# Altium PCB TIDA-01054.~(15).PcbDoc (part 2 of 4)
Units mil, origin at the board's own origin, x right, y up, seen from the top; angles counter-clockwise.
Board outline 4448 x 3930 mil, 4 copper layers (Layer 1 - Top Layer, Layer 2 - GND, Layer 3 - PWR, Layer 4 - Bottom Layer), stack 59.034 mil thick; 537 components, 284 nets, 1540 pads, 769 vias.
Unrouted connection lines stored in the file: 1.

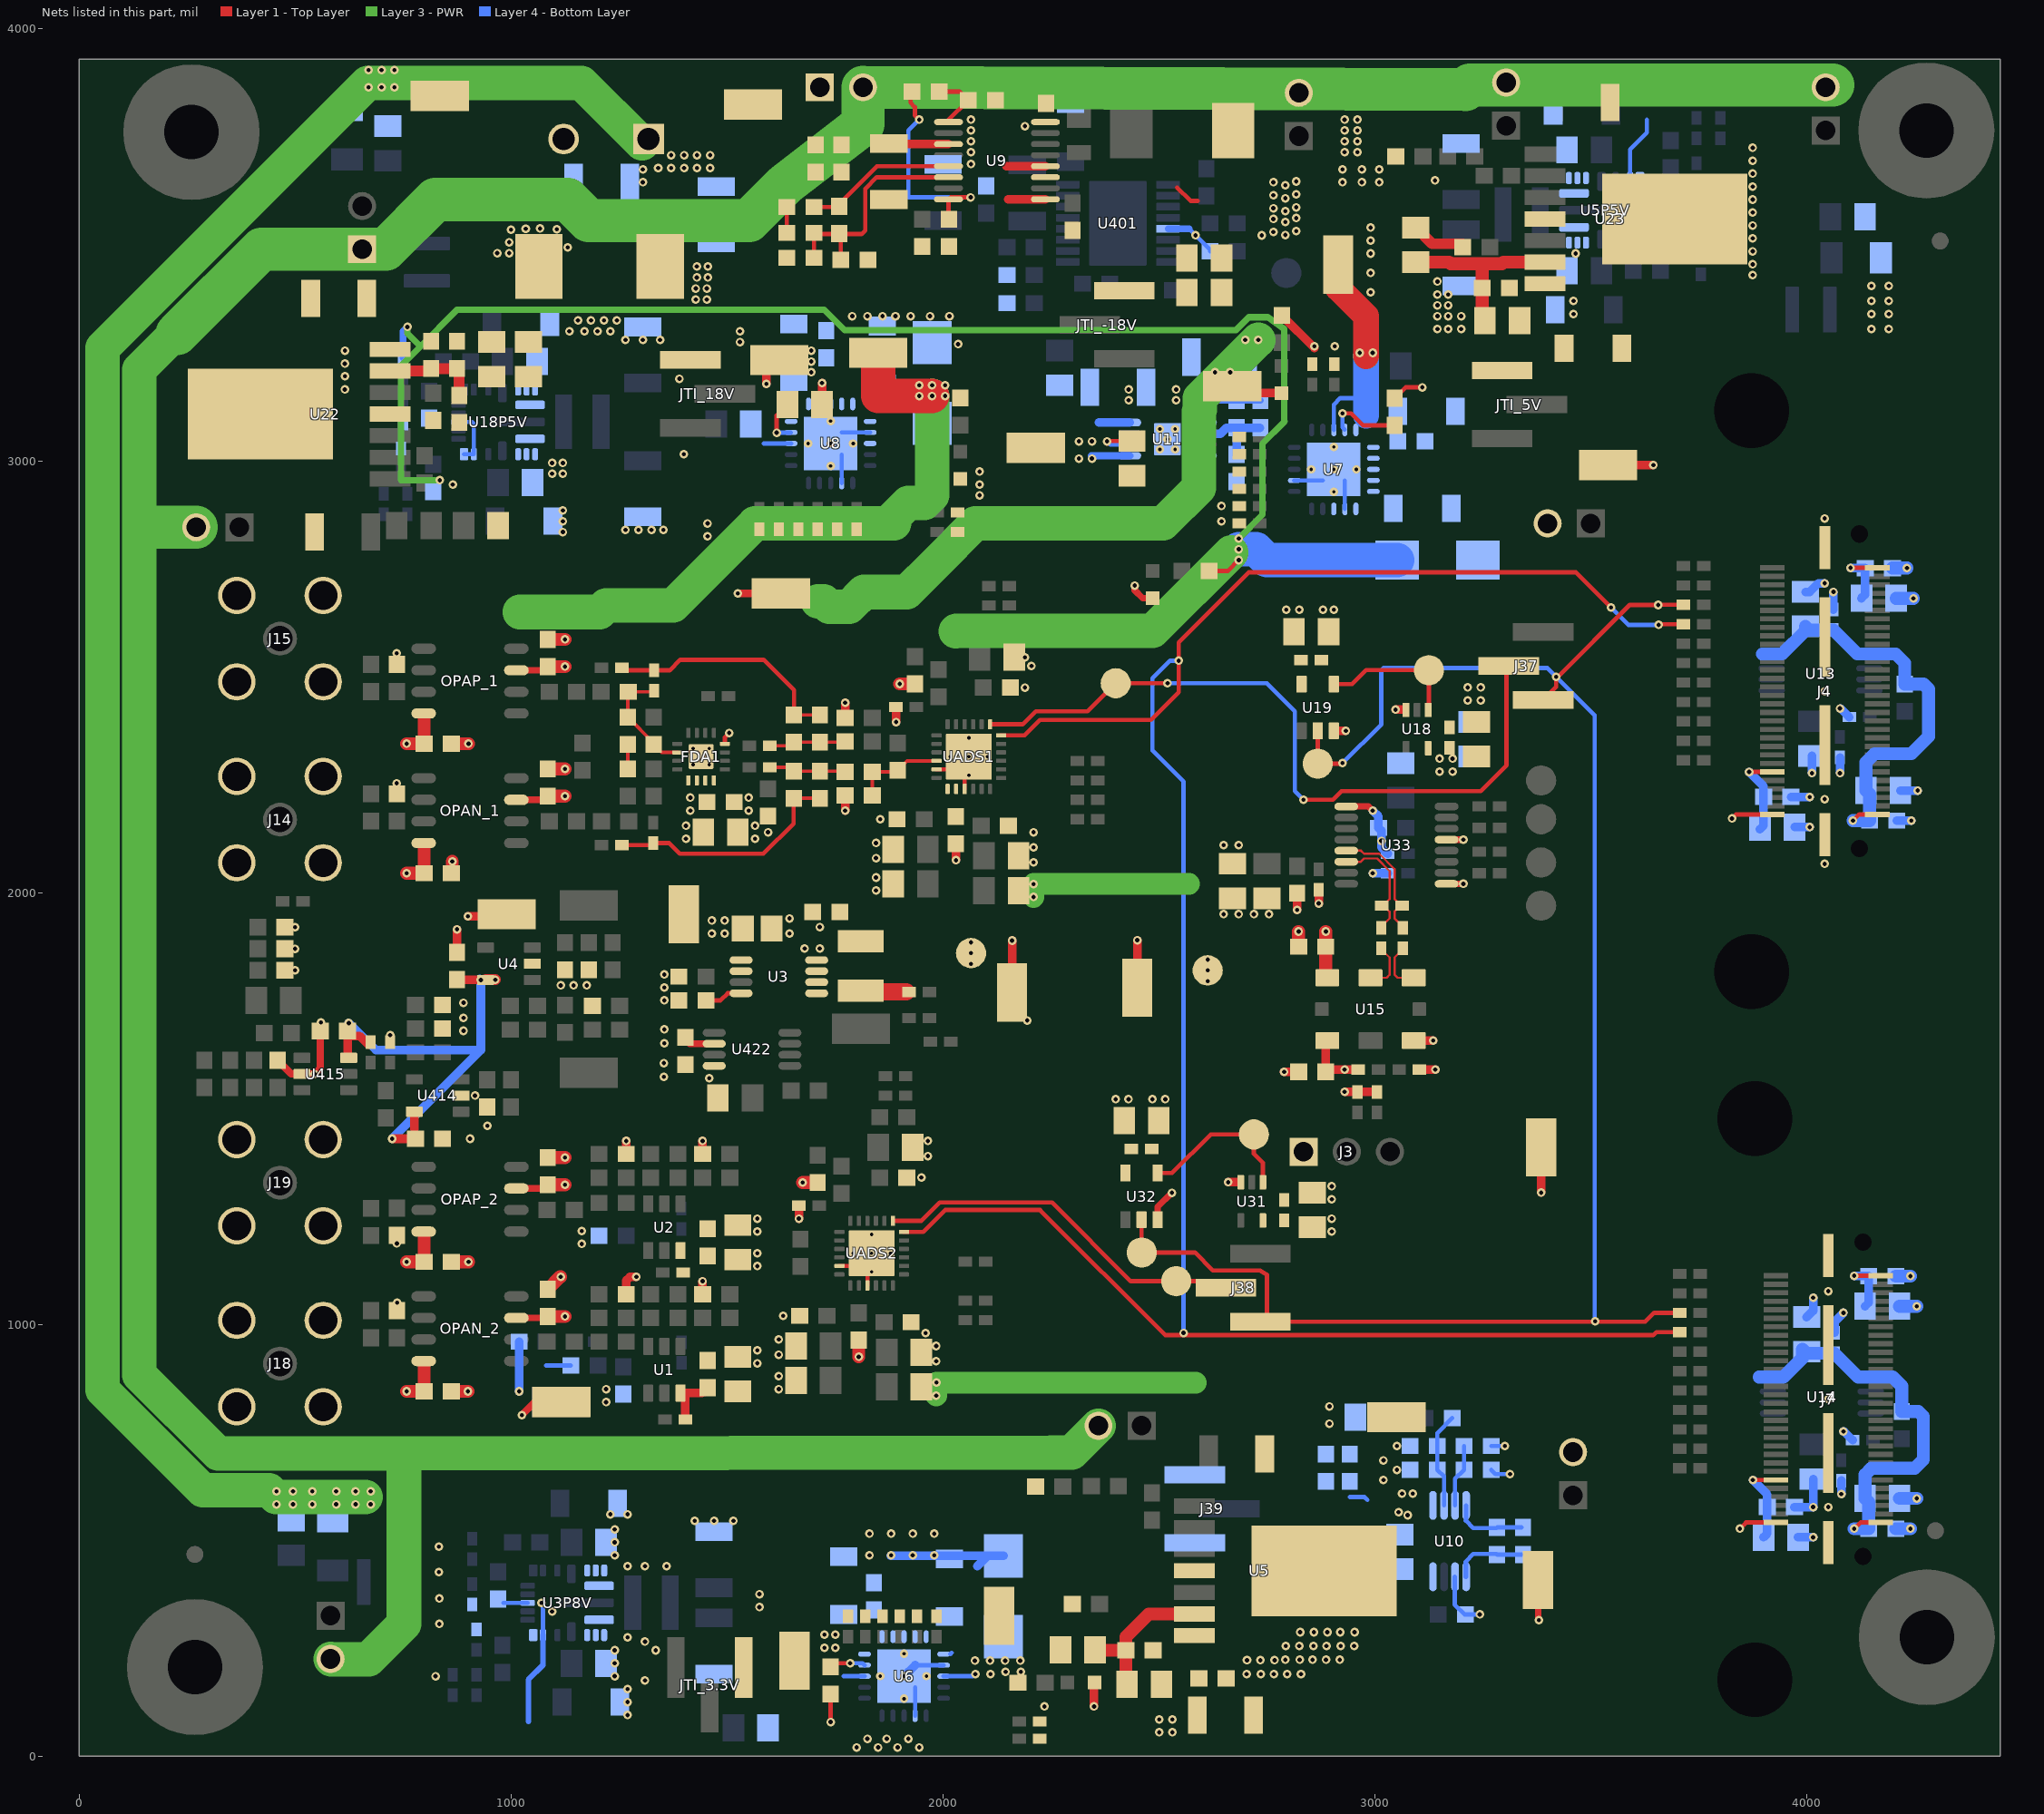
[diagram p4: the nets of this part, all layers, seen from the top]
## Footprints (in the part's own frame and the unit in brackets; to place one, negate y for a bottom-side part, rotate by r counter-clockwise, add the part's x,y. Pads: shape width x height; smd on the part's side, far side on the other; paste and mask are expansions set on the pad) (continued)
RNL0022A_NV [mm] "VQFN, 22 pin, 0.5 mm pitch"
  rrect25% 0.7x0.5 smd paste-0.05 mask-0.05: 1(-1.9,2) 17(1.9,2)
  rrect40% 0.7x0.35 smd paste-0.05 mask-0.05: 2(-1.9,1.425) 3(-1.9,0.575) 15(1.9,0.575) 16(1.9,1.425)
  rrect40% 1.1x0.5 smd paste-0.25 mask-0.05: 4(-1.7,-0.25) 14(1.7,-0.25)
  rrect25% 0.4x0.4 on Bottom Paste: 4A(-2,-0.25) 4B(-1.4,-0.25) 14A(1.4,-0.25) 14B(2,-0.25)
  rrect57% 0.7x0.35 smd paste-0.05 mask-0.05: 5(-1.9,-1.175) 6(-1.9,-1.675) 7(-1.9,-2.175) 11(1.9,-2.175) 12(1.9,-1.675) 13(1.9,-1.175)
  rrect40% 0.5x1.74 smd paste-0.25 mask-0.05: 8(-1,-1.875) 10(1,-1.875)
  rrect25% 0.4x0.66 on Bottom Paste: 8A(-1,-1.445) 8B(-1,-2.305) 10A(1,-1.445) 10B(1,-2.305)
  rrect40% 0.5x3.25 smd paste-0.25 mask-0.05: 9(0,-1.125)
  rrect25% 0.4x0.63 on Bottom Paste: 9A(0,0.12) 9B(0,-0.71) 9C(0,-1.54) 9D(0,-2.37)
  rrect40% 0.35x0.85 smd paste-0.05 mask-0.05: 18(1,2.325) 19(0.5,2.325) 20(0,2.325) 21(-0.5,2.325) 22(-1,2.325)
  silkscreen extent -2.15,-2.65 2.15,2.65, body extent -2,-2.5 2,2.5, height 0.9
Samtec_QTH-030-01-x-D-A [mil] "Header (Shrouded), 19.7mil, 30x2, SMT"
  rect 12x57 smd mask+1: 1(-285.7,121.5) 2(-285.7,-121.5) 3(-266,121.5) 4(-266,-121.5) 5(-246.3,121.5) 6(-246.3,-121.5) 7(-226.6,121.5) 8(-226.6,-121.5) 9(-206.9,121.5) 10(-206.9,-121.5) 11(-187.2,121.5) 12(-187.2,-121.5) 13(-167.5,121.5) 14(-167.5,-121.5) 15(-147.8,121.5) 16(-147.8,-121.5) 17(-128.1,121.5) 18(-128.1,-121.5) 19(-108.4,121.5) 20(-108.4,-121.5) 21(-88.7,121.5) 22(-88.7,-121.5) 23(-69,121.5) 24(-69,-121.5) 25(-49.3,121.5) 26(-49.3,-121.5) 27(-29.6,121.5) 28(-29.6,-121.5) 29(-9.9,121.5) 30(-9.9,-121.5) 31(9.8,121.5) 32(9.8,-121.5) 33(29.5,121.5) 34(29.5,-121.5) 35(49.2,121.5) 36(49.2,-121.5) 37(68.9,121.5) 38(68.9,-121.5) 39(88.6,121.5) 40(88.6,-121.5) 41(108.3,121.5) 42(108.3,-121.5) 43(128,121.5) 44(128,-121.5) 45(147.7,121.5) 46(147.7,-121.5) 47(167.4,121.5) 48(167.4,-121.5) 49(187.1,121.5) 50(187.1,-121.5) 51(206.8,121.5) 52(206.8,-121.5) 53(226.5,121.5) 54(226.5,-121.5) 55(246.2,121.5) 56(246.2,-121.5) 57(265.9,121.5) 58(265.9,-121.5) 59(285.6,121.5) 60(285.6,-121.5)
  round 0 hole 40 unplated mask+1: MH1(-364,80) MH2(364,80)
  rect 100x25 smd mask+1: MP1(-332.7,0) MP4(332.3,0)
  rect 185x25 smd mask+1: MP2(-125.2,0) MP3(124.8,0)
  silkscreen extent -394,-118 394,131, body extent -394,-140 394,140, height 170
Samtec_TMM-103-01-x-S-SM [mm] "Header,2mm, 3x1, SMT"
  rect 1.02x3.56 smd: 1(-2,1.015) 2(0,-1.015) 3(2,1.015)
  silkscreen extent -3.2,-0.99 3,0.99, body extent -3,-2.41 3,2.41, height 5.97
SIA0008B [mm] "SIP 8-Leads, Body 5x7mm"
  rrect17% 1x0.6 on Top Paste: 1(-1.85,2.14) 1(-1.85,2.94) 2(-1.85,-0.4) 2(-1.85,0.4) 3(-1.85,-2.94) 3(-1.85,-2.14) 4(1.85,-2.94) 4(1.85,-2.14) 5(1.85,-0.4) 5(1.85,0.4) 6(1.85,2.14) 6(1.85,2.94)
  rrect10% 1x1.4 smd paste-0.5: 1(-1.85,2.54) 2(-1.85,0) 3(-1.85,-2.54) 4(1.85,-2.54) 5(1.85,0) 6(1.85,2.54)
  rrect12% 0.8x0.8 smd: 7(0,2.865) 8(0,-2.865)
  silkscreen extent -2.64,-3.63 2.64,3.63, body extent -2.56,-3.56 2.56,3.56, height 1.13
SMC [mil] "Molded Diode, 2-Leads, Body 6.9x5.8mm, IPC Medium Density, based on OnSemi component dimensions and land patterns"
  rect 110x150 smd: 1(-140.49,0) 2(140.49,0)
  silkscreen extent -221,-124 189,123, body extent -156,-116 156,116, height 91
Testpoint_Keystone_Miniature [mil] "Miniature SMT test point"
  rect 135x70 smd: 1(0,0)
  silkscreen extent -78,-46 78,45, body extent -52,-20 52,20, height 61
TI_Stacked_Overlay_Small [mil]
  silkscreen extent -418,-98 418,98
TSOP65P640X120-8N [mm] "TSOP, 8-Leads, Body 3.1x4.5mm (max), Pitch 0.65mm, IPC Medium Density"
  oval 1.55x0.35 smd mask+0.08: 1(-2.875,0.975) 2(-2.875,0.325) 3(-2.875,-0.325) 4(-2.875,-0.975) 5(2.875,-0.975) 6(2.875,-0.325) 7(2.875,0.325) 8(2.875,0.975)
  silkscreen extent -1.7,-1.55 1.7,1.55, body extent -2.25,-1.55 2.25,1.55, height 1.21
TZA07A_V [mm] "D2-PAK, 8-Leads, Body 9.9x10.2mm, Pitch 1.27mm, Lead Span 13.8mm, NSC Recommended"
  rect 2.41x0.89 smd: 1(-5.35,3.81) 2(-5.35,2.54) 3(-5.35,1.27) 4(-5.35,0) 5(-5.35,-1.27) 6(-5.35,-2.54) 7(-5.35,-3.81)
  rect 8.54x5.35 smd: 8(2.28,0)
  silkscreen extent -5.47,-5.15 -2.7,5.15, body extent -2.55,-5.2 7.55,5.2, height 4.67
WE-TPC_2828 [mm] "WURTH"
  rect 1x3.2 smd: 1(-1.1,0) 2(1.1,0)
  body extent -1.5,-1.5 1.5,1.5, height 3
WE-TPC_3816 [mm] "WERTH"
  rect 0.5x0.5 smd: 1(-1.75,0) 2(1.75,0.05)
  Layer 1 - Top Layer region: 0.55,2.15 2.15,2.15 2.15,-2.15 0.55,-2.15 0.55,-1.35 0.56,-1.173 1.015,-0.813 1.267,-0.29 1.267,0.29 1.015,0.813 0.56,1.173 0.56,1.173 0.55,1.4
  Layer 1 - Top Layer region: -0.55,-2.15 -2.15,-2.15 -2.15,2.15 -0.55,2.15 -0.55,1.35 -0.56,1.173 -1.015,0.813 -1.267,0.29 -1.267,-0.29 -1.015,-0.813 -0.56,-1.173 -0.56,-1.173 -0.55,-1.4
  silkscreen extent -0.3,-2.15 0.3,2.15, body extent -2.05,-2.05 2.05,2.05, height 1.8
WL-SMCW_RED [mm] "WURTH"
  rect 0.8x0.8 smd: 1(-0.8,0) 2(0.8,0)
  silkscreen extent -1.9,-0.8 1.2,0.8, body extent -0.85,-0.45 0.85,0.45, height 0.8
WURTH_61300211121 [mm] "Header, 2.54mm, 2x1, TH"
  rect 1.65x1.65 hole 1.15: 1(-1.27,0)
  round 1.65 hole 1.15: 2(1.27,0)
  silkscreen extent -2.54,-1.27 2.54,1.6, body extent -2.54,-1.27 2.54,1.27, height 8.54
WURTH_61300311121 [mm] "Header, 2.54mm, 3x1, TH"
  rect 1.65x1.65 hole 1.15: 1(-2.54,0)
  round 1.65 hole 1.15: 2(0,0) 3(2.54,0)
  silkscreen extent -3.81,-1.27 3.81,1.6, body extent -3.81,-1.27 3.81,1.27, height 8.54
Wurth_691213710002 [mm] "TH, 2-Leads, Body 10x8.3mm, Pitch 5mm"
  rect 1.8x1.8 hole 1.3: 1(-2.5,0)
  round 1.8 hole 1.3: 2(2.5,0)
  silkscreen extent -5,-4.75 5,4.15, body extent -5.6,-4.15 5,4.15, height 10
Wurth_WA-SMSI [mm] "ROUND STANDOFF M3 STEEL 5MM"
  round 0 hole 4.4 unplated: ""(0,0)
  Layer 1 - Top Layer region: -3.711,0 -3.666,-0.581 -3.53,-1.147 -3.307,-1.685 -3.003,-2.182 -2.624,-2.624 -2.182,-3.003 -1.685,-3.307 -1.147,-3.53 -0.581,-3.666 0,-3.711 0.581,-3.666 1.147,-3.53 1.685,-3.307 2.182,-3.003 2.624,-2.624 3.003,-2.182 3.307,-1.685 3.53,-1.147 3.666,-0.581 3.711,0 3.7,0 2.466,0 2.418,-0.481 2.278,-0.944 2.05,-1.37 1.744,-1.744 1.37,-2.05 0.944,-2.278 0.481,-2.418 0,-2.466 -0.481,-2.418 -0.944,-2.278 -1.37,-2.05 -1.744,-1.744 -2.05,-1.37 -2.278,-0.944 -2.418,-0.481 -2.466,0 -2.454,0
  Layer 1 - Top Layer region: -3.711,0 -3.666,0.581 -3.53,1.147 -3.307,1.685 -3.003,2.182 -2.624,2.624 -2.182,3.003 -1.685,3.307 -1.147,3.53 -0.581,3.666 0,3.711 0.581,3.666 1.147,3.53 1.685,3.307 2.182,3.003 2.624,2.624 3.003,2.182 3.307,1.685 3.53,1.147 3.666,0.581 3.711,0 3.7,0 2.466,0 2.418,0.481 2.278,0.944 2.05,1.37 1.744,1.744 1.37,2.05 0.944,2.278 0.481,2.418 0,2.466 -0.481,2.418 -0.944,2.278 -1.37,2.05 -1.744,1.744 -2.05,1.37 -2.278,0.944 -2.418,0.481 -2.466,0 -2.454,0
  silkscreen extent -4.1,-4.1 4.1,4.1, body extent -3,-3 3,3, height 5

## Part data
24Vin GNDin TP3 TP8 TP25 TP26 TP27 TP28 TP29 TP30 TP_3P3V TP_3P8V TP_5P5V TP_18P5V TPAGND1 TPAGND2 TPAGND3 TPAGND4 TPGND1 TPGND2 TPGND3 TPGND4 TPV4: "Test Point, Miniature, SMT"
C1 C43 C47 C354 C389 C391 C408 Cin Cin1 Cin2 Cin3 Cout2: "CAP, CERM, 10 µF, 50 V, +/- 10%, X7R, 1210"
C3: "CAP, CERM, 10uF, 10V, +/-10%, X7R, 0805"
C4: "CAP, CERM, 1uF, 10V, +/-10%, X7R, 0603"
C5: "CAP, CERM, 47 µF, 10 V, +/- 10%, X7R, 1210"
C9 C12 C13 C16 C17 C20 Cout4: "CAP, CERM, 47 µF, 25 V, +/- 20%, X5R, 1206_190"
C10: "CAP, CERM, 1000 pF, 100 V, +/- 10%, X7R, AEC-Q200 Grade 1, 0603"
C11 C42 C45 Cout3: "CAP, CERM, 1 µF, 100 V, +/- 10%, X7S, 0805"
C14 C18: "CAP, CERM, 1000 pF, 50 V, +/- 1%, C0G/NP0, 0603"
C15 C19 C318 C319 C321 C339 C348 C453 Cout6 CR479: "CAP, CERM, 1 µF, 25 V, +/- 10%, X7R, 0603"
C21 C22 C57 C58 C59 C60 C261 C262 C271 C272 C284 C287 C288 C289 C290 C291 C304 C305 C306 C307 C308 C338 C343 C345 C347 CR481: "CAP, CERM, 10 µF, 10 V, +/- 10%, X7R, 0805"
C23 C24 C33: "CAP, CERM, 10 µF, 10 V, +/- 20%, X5R, 0603"
C25: "CAP, CERM, 0.47 µF, 25 V, +/- 10%, X7R, 0603"
C26 C28: "CAP, CERM, 22 µF, 6.3 V, +/- 20%, X5R, 0603"
C27: "CAP, CERM, 0.1 µF, 16 V, +/- 10%, X5R, 0603"
C29: "CAP, CERM, 4.7 µF, 10 V, +/- 20%, X5R, 0603"
C30: "CAP, CERM, 0.22 µF, 10 V, +/- 10%, X5R, 0603"
C31: "CAP, CERM, 0.22 µF, 50 V, +/- 10%, X7R, AEC-Q200 Grade 1, 0603"
C32 C35: "CAP, CERM, 0.1 µF, 50 V, +/- 10%, X7R, 0603"
C34: "CAP, CERM, 0.033 µF, 50 V, +/- 10%, X7R, 0603"
C37: "CAP, CERM, 910 pF, 50 V, +/- 5%, C0G/NP0, 0603"
C38: "CAP, CERM, 10 pF, 50 V, +/- 5%, C0G/NP0, AEC-Q200 Grade 1, 0603"
C39: "CAP, CERM, 150 pF, 50 V, +/- 5%, C0G/NP0, 0603"
C40: "CAP, CERM, 0.022 µF, 50 V, +/- 10%, X7R, 0603"
C41: "CAP, CERM, 22 µF, 35 V, +/- 20%, X5R, 0805"
C46: "CAP, CERM, 0.01 µF, 50 V, +/- 10%, X7R, AEC-Q200 Grade 1, 0603"
C53 C54 C55 C56 C94 C95 C340 C344 C346 C349 C350: "CAP, CERM, 0.1 µF, 16 V, +/- 10%, X7R, 0402"
C61 C84 C85 C91 C92 C93 C108 C112 C116 C120 C121 C122 C259 C260 C266 C267 C268 C269 C320 C454 C455 C460: "CAP, CERM, 0.1 µF, 25 V, +/- 5%, X7R, 0603"
C62 C449 C457 C458 C459: "CAP, CERM, 10 µF, 10 V, +/- 10%, X7T, 0603"
C63 C64: "CAP, CERM, 0.1 µF, 25 V, +/- 10%, X5R, 0402"
C71 C72 C96 C97: "CAP, CERM, 100 pF, 100 V, +/- 5%, C0G/NP0, AEC-Q200 Grade 1, 0603"
C79 C80 C81 C82 C104 C105 C106 C107: "CAP, CERM, 0.1 µF, 100 V, +/- 10%, X7R, 0603"
C83 CMFB: "CAP, CERM, 68 pF, 100 V, +/- 5%, C0G/NP0, 0603"
C86 C87 C111 C114: "CAP, CERM, 390 pF, 50 V, +/- 5%, C0G/NP0, 0603"
C88 C119: "CAP, CERM, 1 µF, 10 V, +/- 10%, X7R, 0603"
C89 C90 C117 C118 C315 C316 C317: "CAP, CERM, 1000 pF, 100 V, +/- 5%, C0G/NP0, 0603"
C109 C115: "CAP, CERM, 1000 pF, 50 V, +/- 5%, C0G/NP0, 0603"
C110 C113: "CAP, CERM, 130 pF, 100 V, +/- 5%, C0G/NP0, 0603"
C322 C323: "CAP, CERM, 22 µF, 10 V, +/- 20%, X5R, 0603"
C335: "CAP, CERM, 0.01 µF, 50 V, +/- 5%, C0G/NP0, AEC-Q200 Grade 1, 0603"
C351 C352 C353: "CAP, TA, 4.7 µF, 25 V, +/- 10%, 2 ohm, SMD"
C355 C359 C360 C367 C371 C372 C379 C383 C384: "CAP, CERM, 0.1 µF, 100 V, +/- 10%, X7R, 0805"
C356 C368 C380: "CAP, CERM, 4.7 µF, 35 V, +/- 10%, X7R, 1206"
C357 C358 C369 C370 C381 C382: "CAP, CERM, 10 µF, 25 V, +/- 10%, X7R, 1206"
C361 C373 C385: "CAP, CERM, 0.47 µF, 25 V, +/- 10%, X7R, AEC-Q200 Grade 1, 0603"
C362 C375 C388: "CAP, CERM, 0.1 µF, 50 V, +/- 10%, X6S, 0402"
C363 C374 C387: "CAP, CERM, 100 pF, 25 V, +/- 5%, C0G/NP0, 0402"
C364 C366 C376 C378: "CAP, CERM, 22 µF, 16 V, +/- 20%, X7R, AEC-Q200 Grade 1, 1210"
C401: "CAP, CERM, 10 µF, 50 V, +/- 10%, X7S, 1210"
C402: "CAP, CERM, 0.1 µF, 50 V, +/- 10%, X5R, 0603"
C403: "CAP, CERM, 4.7 µF, 25 V, +/- 10%, X5R, 0603"
C404: "CAP, CERM, 0.47 µF, 50 V, +/- 10%, X5R, 0603"
C405: "CAP, CERM, 1 µF, 35 V, +/- 10%, X7R, 0603"
C406: "CAP, CERM, 22 µF, 35 V, +/- 20%, X5R, 1206"
C407: "CAP, CERM, 0.022 µF, 25 V, +/- 10%, X7R, 0603"
C409: "CAP, CERM, 100 pF, 50 V, +/- 5%, C0G/NP0, 0603"
C452: "CAP, CERM, 0.22 µF, 16 V, +/- 5%, X7R, 0805"
C461: "CAP, CERM, 10 pF, 50 V, +/- 1%, C0G/NP0, 0603"
Cff: "CAP, CERM, 0.022 µF, 100 V, +/- 10%, X7R, 0603"
Cff2 Cff3: "CAP, CERM, 0.022uF, 50V, +/-10%, X7R, 0805"
Cout1: "CAP, CERM, 22 µF, 35 V, +/- 20%, JB, 0805"
Cout5: "CAP, CERM, 100 µF, 6.3 V, +/- 20%, X6S, 1210"
Css: "CAP, CERM, 4700 pF, 100 V, +/- 10%, X7R, AEC-Q200 Grade 1, 0603"
Css2 Css3: "CAP, CERM, 0.01 µF, 6.3 V, +/- 10%, X7R, 0603"
CVCC3V CVCC5V CVCC18V: "CAP, CERM, 2.2 µF, 6.3 V, +/- 10%, X7R, AEC-Q200 Grade 1, 0603"
D1: "Diode, Schottky, 200 V, 4 A, SMC"
D2: "Diode, Schottky, 100 V, 1 A, PowerDI123"
D14 D18 D21 D22: "LED, Red, SMD"
FDA1: "Low Power, Precision, 160MHz, Fully Differential Amplifier, RGT0016A"
FID1 FID2 FID3 FID4 FID5 FID6: "Fiducial mark.  There is nothing to buy or mount."
H1 H2 H3 H4: "Machine Screw, Round, #4-40 x 1/4, Nylon, Philips panhead"
H5 H6 H7 H8: "Standoff, Hex, 0.5\"L #4-40 Nylon"
H9 H11 H13 H15: "ROUND STANDOFF M3 STEEL 5MM"
J3: "Header, 2.54 mm, 3x1, Gold, TH"
J4 J7: "Header(Shrouded), 19.7mil, 30x2, Gold, SMT"
J5 J6 JMTI_-18V JPRI_-18V JSI_3.3V JSI_5V JSI_18V JZI_3.3V JZI_5V JZI_18V: "Header, 2.54 mm, 2x1, Gold, TH"
J8: "Terminal Block, 2x1, Brass, TH"
J14 J15 J18 J19: "SMA Straight Jack, Gold, 50 Ohm, TH"
J37 J38 J39 JTI_3.3V JTI_5V JTI_18V JTI_-18V: "Header, 2mm, 3x1, Gold, SMT"
L1: "Inductor, Shielded Drum Core, Ferrite, 330 µH, 0.42 A, 1.59 ohm, SMD"
L4 L5 L6 L7 L8 L9 L10 L12 L16 L17 L18 L19: "Ferrite Bead, 600 ohm @ 100MHz, 2A, 0805"
L20 L22 L24: "Inductor, Wirewound, Ferrite, 3.3 µH, 1.21 A, 0.096 ohm, AEC-Q200 Grade 2, SMD"
L21 L23 L25: "Inductor, Shielded Drum Core, Ferrite, 6.8 µH, 1.1 A, 0.142 ohm, SMD"
L401: "Inductor, Shielded Drum Core, Metal Composite, 68 µH, 0.22 A, 1.15 ohm, SMD"
Logo1: library part TI_Logo, "Texas Instrument Corporate Signature"
Logo2: library part Pb-Free
NT1 NT2: "Single point connection between nets."
OPAN_1 OPAN_2 OPAP_1 OPAP_2: "Low-Noise, High-Precision, JFET-Input OPERATIONAL AMPLIFIER, D0008A"
R3 R4: "RES, 0.22 ohm, 1%, 0.1W, 0603"
R8 R9 R10 R11 R12 R13 R14 R15 R17 R18 R19 R20 R24 R25 R26 R27 R29 R30 R31 R32 R33 R34 R35 R36 R56 R65 R66 R67 R68 R69 R70 R71 R72 R73 R74 R75 R76 R77 R78 R79 R80 R81 R82 R83 R84 R85 R86 R211 R212 R213 R223 R225 R226 R232 R233 R234 R235 R240 R248 R250 R252 R255 R259 R260 R262 R263 R279 R280 R284 R288 R453 R454 R457 RB3 RB5 RB18 REN0 REN1 RMFBN RMFBN2 RMFBP RMFBP2 RR457: "RES, 0, 5%, 0.063 W, 0402"
R21 RDN1 RDN3 RDP1 RDP3: "RES, 0, 5%, 0.1 W, 0603"
R22: "RES, 4.70, 0.5%, 0.1 W, 0603"
R40: "RES, 215 k, 0.1%, 0.1 W, 0603"
R41: "RES, 23.2 k, 0.1%, 0.1 W, 0603"
R42: "RES, 1.65 k, 0.1%, 0.1 W, 0603"
R43: "RES, 30.9 k, 0.1%, 0.1 W, 0603"
R44: "RES, 2.15 k, 0.1%, 0.1 W, 0603"
R45: "RES, 52.3 k, 0.1%, 0.1 W, 0603"
R46: "RES, 910, 5%, 0.1 W, 0603"
R47: "RES, 18.0 k, 0.1%, 0.1 W, 0603"
R50 R216: "RES, 20.0 k, 0.1%, 0.1 W, 0603"
R64 R87: "RES, 10.0 k, 1%, 0.1 W, 0603"
R88 R89 R90 R91: "RES, 4.7 k, 5%, 0.063 W, 0402"
R92: "RES, 100, 5%, 0.063 W, 0402"
R95 R256 R257 R278: "RES, 33, 5%, 0.063 W, 0402"
R97 R98 R100 R101 R107 R108 R110 R114 R116 R214 R485 R491 RDN2 RDN4 RDP2 RDP4: "RES, 1.00 k, 0.1%, 0.1 W, 0603"
R99: "RES, 249, 1%, 0.1 W, 0603"
R103 R104 R115 R117: "RES, 20.0, 0.1%, 0.1 W, 0603"
R112 R113: "RES, 124, 1%, 0.1 W, 0603"
R215 R492: "RES, 499, 0.1%, 0.1 W, 0603"
R217 R218 R246 R247: "RES, 49.9 k, 0.1%, 0.1 W, 0603"
R258 R261: "RES, 10.0 k, 0.1%, 0.1 W, 0603"
R268 R269: "RES, 1.00, 1%, 0.1 W, 0603"
R290: "RES, 36 k, 5%, 0.063 W, 0402"
R291 R295 R298: "RES, 100 k, 1%, 0.063 W, 0402"
R294: "RES, 22.6 k, 1%, 0.063 W, 0402"
R297: "RES, 5.62 k, 0.1%, 0.063 W, 0402"
R401: "RES, 58.3 k, 0.1%, 0.1 W, 0603"
R402: "RES, 1.00 M, 1%, 0.1 W, 0603"
R404: "RES, 80.6 k, 1%, 0.1 W, 0603"
R486: "RES, 2.49 k, 0.1%, 0.1 W, 0603"
R488: "RES, 4.99 k, 0.1%, 0.1 W, 0603"
R489: "RES, 4.75, 1%, 0.1 W, 0603"
R494: "RES, 30.0 k, 0.1%, 0.1 W, 0603"
Renb: "RES, 20.5 k, 1%, 0.125 W, 0805"
Renb2 Renb3: "RES, 3.57 k, 0.1%, 0.1 W, 0603"
Rent: "RES, 118k ohm, 0.1%, 0.125W, 0805"
Rent2 Rent3: "RES, 68.1 k, 0.1%, 0.1 W, 0603"
RES3V RES5V RES18V: "RES, 100 k, 0.1%, 0.1 W, 0603"
Rfbb: "RES, 1.50 k, 0.1%, 0.1 W, 0603"
Rfbb3 Rfbb5: "RES, 1.07 k, 0.1%, 0.125 W, 0805"
Rfbt: "RES, 34.0 k, 0.1%, 0.1 W, 0603"
Rfbt2: "RES, 6.34 k, 0.1%, 0.063 W, 0603"
Rfbt3: "RES, 4.02 k, 0.1%, 0.1 W, 0603"
Ron: "RES, 383 k, 0.1%, 0.1 W, 0603"
Ron2: "RES, 113 k, 0.1%, 0.1 W, 0603"
Ron3: "RES, 78.7 k, 0.1%, 0.1 W, 0603"
RR413: "RES, 0.22, 1%, 0.1 W, 0603"
TP1 TP2 TP4 TP7 TP16 TP31 TP32 TP33 TP34 TP35 TPAGND TPGND TPPGOOD: library part PogoPad, "Pad for Pogo Pin Connector"
U1 U2: "High Bandwidth, High Precision, Low Noise and Distortion Amplifier with Ultra-Fast Transition time Low Power mode, DBV0006A"
U3: "High-Precision Voltage Reference with Integrated High-Bandwidth Buffer, DGK0008A"
U3P8V U5P5V U18P5V: "3.5A Synchronous Buck Regulator for Automotive Applications, RNL0022A (VQFN-HR-22)"
U4: "Precision, Low Noise, Low Iq Operational Amplifier, 2.2 to 5.5 V, -40 to 125 degC, 5-pin SOT23 (DBV0005A), Green (RoHS & no Sb/Br)"
U5: "2A SIMPLE SWITCHER® Power Module with 42V Maximum Input, 7 pin TO-PMOD"
U6 U7 U8: "36-V, 1-A, 4.17-µVRMS, RF LDO Voltage Regulator, RGW0020A"
U9: "SIMPLE SWITCHER® 75V, 0.5A Step-Down Switching Regulator, 16-pin TSSOP"
U10: "Low Noise Negative Bias Generator, 8-pin Mini SOIC, Pb-Free"
U11: "Single Output High PSRR LDO, 200 mA, Adjustable -1.18 to -33 V Output, -3 to -36 V Input, with Ultra-Low Noise, 8-pin MSOP (DGN), -55 to 125 degC, Green (RoHS & no Sb/Br)"
U13 U14: "I2C BUS EEPROM (2-Wire), TSSOP-B8"
U15: "Ultra-Low Jitter Programmable Oscillator with Internal EEPROM, SIA0008B"
U18 U31: "LOW-POWER SINGLE POSITIVE-EDGE-TRIGGERED D-TYPE FLIP-FLOP, DCK0005A"
U19 U32: "SINGLE SCHMITT-TRIGGER INVERTER GATE, DBV0005A"
U22: "1A SIMPLE SWITCHER® Power Module with 42V Maximum Input, 7 pin TO-PMOD"
U23: "3A SIMPLE SWITCHER® Power Module with 42V Maximum Input Voltage, 7-pin TO-PMOD, Pb-Free"
U33: "Low Skew, 1-to-4 Multiplexed Differential/LVCMOS-to-LVCMOS/TTL Fanout Buffer, PW0016A"
U401: "SIMPLE SWITCHER 3.5 V to 60 V 1 A Synchronous Step-Down Voltage Converter, PWP0016G (TSSOP-16)"
U414: "Low-Noise, 900 kHz, RRIO, Precision Operational Amplifier, Zerø-Drift Series, 2.2 to 5.5 V, -40 to 125 degC, 5-pin SOT23 (DBV0005A), Green (RoHS & no Sb/Br)"
U415: "High-Bandwidth, High-Precision, Low THD+N, 16-Bit and 18-Bit Analog-to-Digital Converter (ADC) Drivers, DBV0006A"
U422: "Low Noise, Very Low Drift, Precision Voltage Reference, -40 to 125 degC, 8-pin MSOP (DGK), Green (RoHS & no Sb/Br)"
UADS1 UADS2: "20-Bit, High-Speed SAR ADCs With Integrated Reference Buffer, Integrated LDO, and multiSPI Digital Interface, RGE0024H (VQFN-24)"
ZZ2 ZZ3 ZZ4: library part AssemblyNote

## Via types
v1: diameter 20, hole 10, Layer 1 - Top Layer to Layer 4 - Bottom Layer, tented both sides, 381 vias
v2: diameter 20, hole 10, Layer 1 - Top Layer to Layer 4 - Bottom Layer, 258 vias
v3: diameter 20, hole 10, Layer 1 - Top Layer to Layer 4 - Bottom Layer, tented bottom, 57 vias
v4: diameter 19.68, hole 7.87, Layer 1 - Top Layer to Layer 4 - Bottom Layer, tented both sides, 48 vias
v5: diameter 20, hole 10, Layer 1 - Top Layer to Layer 4 - Bottom Layer, tented top, 19 vias
v6: diameter 19.68, hole 7.87, Layer 1 - Top Layer to Layer 4 - Bottom Layer, 6 vias

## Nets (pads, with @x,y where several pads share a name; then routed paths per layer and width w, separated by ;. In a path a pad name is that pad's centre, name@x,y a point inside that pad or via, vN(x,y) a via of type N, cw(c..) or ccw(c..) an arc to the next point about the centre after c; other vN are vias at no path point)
3.3V: C20.1 C61.1 C62.1 C94.2 C95.2 C290.1 C291.2 C338.1 C343.1 C344.2 C345.2 C346.2 C347.1 C353.1 L4.2 L7.1 L9.1 L10.2 L12.2 R46.2 R88.2 R89.2 R91.1 TP_3P3V.1 U6.1 U6.3 U6.20 U15.1@2890,1656.91 U15.6@2890,1802.58 U18.5 U19.5 U31.5 U32.5 | length 1429.3
  Layer 1 - Top Layer w20: U15.1@2886.5,1653.41 C62.1@2886.5,1584.75 2891.5,1589.75 v1(2930,1589.75) R91.1@2961.38,1589.75 ; v1(2930,1538.37) R88.2@2960,1538.37 R89.2@3005,1538.37
  Layer 1 - Top Layer w30: v1(2886.5,1909.74) C61.1@2886.5,1874.74 2886.5,1806.08 U15.6@2890,1802.58
  Layer 3 - PWR w50: v1(1984.45,834.74) 1984.45,864.19 v1(1985.25,865) 2585,865 ; v1(2210,1989.75) v1(2210,2019.75) 2210.25,2020 2570,2020
  Layer 4 - Bottom Layer w10: U6.3@2001.54,185 2070,185 v1(2075,190) ; 2017.09,236.18 2020,239.09
  other v1: 2110,190 2145.02,195 2180.21,195.21 2073.93,221.07 2108.93,221.07 2143.93,221.07 2178.93,221.07 3076.04,558 3055,565 2900.21,1214.75 2900.21,1244.75 2399.83,1521.3 2429.83,1521.3 2650,1949.74 2685,1949.74 2720,1949.74 2755,1949.74 3150,2280.04 3180,2280.04 3150,2310.04 3180,2310.04 2795,2654.75 2825,2654.75
3.8V: C17.1 C18.1 L19.2 TP_3P8V.1 U6.13 U6.15 U6.16 | length 48.5
  Layer 4 - Bottom Layer w10: 1770,185 U6.13@1818.46,185
  other v1: 1725.51,251 1751,251 1725.51,281 1751,281
5.5V: C13.1 C14.1 L18.2 TP_5P5V.1 U7.13 U7.15 U7.16 | length 441.6
  Layer 1 - Top Layer w60: TP_5P5V.1@2915,3400 2980,3335 2980,3242.5
  Layer 4 - Bottom Layer w10: U7.13@2905,3071.54 2905,3130 2920,3145 2960,3145
  Layer 4 - Bottom Layer w60: 2980,3105 L18.2@2980,3220 L18.2@2980,3242.5
  other v3: 2965,3250 2995,3250
5V: C3.2 C16.1 C85.1 C112.2 C116.2 C284.1 C304.1 C305.1 C320.2 C352.1 C449.2 C455.2 CR479.1 FDA1.5 FDA1.6 FDA1.7 FDA1.8 FDA1.12 L6.1 L8.1 R47.2 R453.1 RB18.2 REN0.1 REN1.1 RES18V.1 TP8.1 U1.6 U2.6 U3.1 U3.2 U4.5 U7.1 U7.3 U7.20 U414.5 U415.6 U422.2 | length 5611.6
  Layer 1 - Top Layer w10: U4.5@940.87,1797.6 U4.5@941.34,1798.08 ; FDA1.12@1495.12,2345.75 1495.12,2359.86 v1(1505,2369.75) ; R47.2@2616.5,2745 2660,2745 v1(2685,2770)
  Layer 1 - Top Layer w15: CR479.1@1413.8,1649.8 U422.2@1470.4,1649.8
  Layer 1 - Top Layer w20: C449.2@621.32,1679.02 C449.2@621.53,1678.81 ; U415.6@621.53,1616.87 C449.2@621.53,1678.81 ; R453.1@669.83,1647.64 649.46,1668 632.34,1668 C449.2@621.53,1678.81 ; v2(724.51,1429.75) C455.2@778.5,1429.75 ; 775.87,1452.38 U414.5@775.87,1492.34 ; C320.2@875,1796.24 876.36,1797.6 v1(930,1797.6) ; U1.6@1392.4,840.61 1442.36,840.61 C112.2@1455,853.25 ; REN0.1@1403.62,779.75 U1.6@1403.62,828.37
  Layer 1 - Top Layer w25: U4.5@941.34,1798.08 v1(963.52,1798.08)
  Layer 3 - PWR w15: v3(760,3310) 760,3295 790,3265 ; v2(835,2955) 745,2955 745,3220 790,3265 ; v1(2685,2820) 2740,2875 2740,3040 2789.9,3089.9 ; 2791.19,3091.19 2789.9,3089.9 ; 790,3265 875,3350 1725,3350 1772.5,3302.5 2678.25,3302.5 2708.25,3332.5 2751.75,3332.5 2789.9,3305.9 2789.9,3089.9
  Layer 3 - PWR w80: 2030,2604.75 2031.02,2605.77 2485.9,2605.77 2667.41,2787.28
  Layer 4 - Bottom Layer w15: RB18.2@750,3238.62 750,3300 v3(760,3310)
  Layer 4 - Bottom Layer w20: v2(624.28,1697.72) 686.76,1635.24 930,1635.24 ; v2(724.51,1429.75) 930,1635.24 ; v1@927.86,1799.75 v1(930,1797.6) 930,1635.24
  Layer 4 - Bottom Layer w80: v1(2685,2795) 2725,2795 2750,2770 C352.1@3051.5,2770
  other v1: 1620,849.75 1620,879.75 1570,1134.75 1570,1164.75 1464.79,1905.16 1494.79,1905.16 1464.79,1935.16 1494.79,1935.16 1845,2004.75 1845,2034.75 1405,2124.75 1405,2154.75 1415,2189.75 1415,2219.75
  other v2: 1355,1651 1355,1683
18.5V: C9.1 C10.1 L16.1 TP_18P5V.1 U8.13 U8.15 U8.16 | length 130.9
  Layer 1 - Top Layer w20: v2(1591,3178) 1591,3203 TP_18P5V.1@1621,3233
  Layer 4 - Bottom Layer w10: 1585,3040 U8.13@1648.46,3040
  other v2: 1695,3205 1695,3230 1695,3255
1050_3.3V: Cff3.1 Cout5.1 Cout6.1 JTI_3.3V.3 Rfbt3.2 U5.7
  other v2: 1800,20 1850,20 1895,20 1945,20 1825,40 1870,40 1920,40 2501,55 2531,55 2501,85 2531,85
1050_5V: Cff2.1 Cout4.1 JTI_5V.3 Rfbt2.2 U23.7
1050_18V: Cff.1 Cout1.1 Cout2.1 Cout3.1 JTI_18V.3 Rfbt.2 U22.7
1050_-18V: C34.2 C35.2 C37.2 C41.2 C42.2 C43.2 JTI_-18V.1 R42.1 R50.1 U9.9 U9.12 | length 176
  Layer 1 - Top Layer w20: 2147.2,3682.2 U9.12@2237.2,3682.2 ; 2151.2,3605.43 U9.9@2237.2,3605.43
+18V: C12.1 C79.2 C81.2 C104.2 C106.2 C351.1 OPAN_1.7 OPAN_2.7 OPAP_1.7 OPAP_2.7 R247.2 TP3.1 U8.1 U8.3 U8.20 | length 1981.4
  Layer 1 - Top Layer w15: OPAN_2.7@1012.28,1014.75 1081.5,1014.75 C104.2@1085,1018.25 ; OPAP_2.7@1012.28,1314.75 1081.5,1314.75 C106.2@1085,1318.25 ; OPAN_1.7@1012.28,2214.74 1076.5,2214.74 C81.2@1085,2223.25 ; OPAP_1.7@1012.28,2514.75 1076.5,2514.75 C79.2@1085,2523.25
  Layer 1 - Top Layer w30: C104.2@1085,1018.25 v1(1125,1018.25) ; C106.2@1085,1323.25 v1(1125,1323.25) ; C81.2@1085,2223.25 v1(1125,2223.25) ; C79.2@1085,2523.25 v1(1125,2523.25)
  Layer 1 - Top Layer w80: TP3.1@1850,3240 1850,3150 v1(1945,3150) v1(1975,3150)
  Layer 3 - PWR w80: 1020,2649.75 1205,2649.75 1220.25,2665 1375,2665 1565,2855 1887,2855 1887,2869.78 1919.22,2902 1957,2902 1975,2920 v1(1975,3150)
  other v1: 2005,3150 1945,3175 1975,3175 2005,3175
+24VDC: Cin.1 D1.1 JMTI_-18V.2 JPRI_-18V.2 JSI_3.3V.2 JSI_5V.2 JSI_18V.1 JZI_3.3V.2 JZI_5V.2 JZI_18V.2 | length 9642
  Layer 3 - PWR w10: 1810,3775 1815,3780
  Layer 3 - PWR w80: 227,3295 223,3295 139,3211 139,883 321.47,700.53 569.85,700.53 569.98,700.66 752,700.91 752,306 670,224 583,224 JSI_3.3V.2@582,225 ; 759,700.92 2250,703 2298,703 JZI_3.3V.2@2360,765
  Layer 3 - PWR w100: 149,2844 151,2846 JZI_18V.2@271,2846 ; 227,3295 422,3490 JSI_18V.1@655,3490 710,3490 825,3605 1131,3605 1180,3556 1551,3556 1635,3640 1810,3775 ; 1815,3780 JMTI_-18V.2@1815,3865 3210,3860 3220,3870 JSI_5V.2@4060,3870
  other v1: 1427.8,3373.53 1453.28,3373.53 1427.8,3399.02 1453.28,3399.02 1430,3424.51 1455.49,3424.51 1430,3450 1455.49,3450
+24VDC_IN: 24Vin.1 C1.1 D1.2 J8.2
  other v1: 968,3481 995.62,3481 1131,3494 995.62,3506 1000,3535 1106,3536 1034,3537 1067,3538
-0.2V: C23.1 C24.1 J39.1 L5.1 TP27.1
  other v1: 2895,770 2895,810
-18.5V: C354.1 L17.1 TP25.1 U11.5 U11.8 | length 159.8
  Layer 4 - Bottom Layer w17: v5@2343.39,3011.61 U11.5@2432.4,3011.61
  Layer 4 - Bottom Layer w20: 2361.61,3088.39 U11.8@2432.4,3088.39
  other v2: 2315,3045
  other v3: 2315,3005
  other v5: 2345,3005 2345,3045
-18V: C46.1 C47.1 C80.2 C82.2 C105.2 C107.2 D21.1 OPAN_1.4 OPAN_2.4 OPAP_1.4 OPAP_2.4 R43.2 TP26.1 U11.1 | length 2075.2
  Layer 1 - Top Layer w10: TP26.1@2695,3170 TP26.1@2708.26,3156.74
  Layer 1 - Top Layer w20: TP26.1@2708.26,3156.74 D21.1@2783.32,3156.74
  Layer 1 - Top Layer w30: v1(758.5,844.75) C105.2@798.5,844.75 OPAN_2.4@798.5,909.75 ; v1(758.5,1144.75) C107.2@798.5,1144.75 OPAP_2.4@798.5,1209.75 ; v1(758.5,2044.74) C82.2@798.5,2044.74 OPAN_1.4@798.5,2109.74 ; v1(758.5,2344.75) C80.2@798.5,2344.75 OPAP_1.4@798.5,2409.75
  Layer 3 - PWR w80: 1710,2674.75 1724.22,2674.75 1737.22,2661.75 1782.78,2661.75 1817.04,2696 1916,2696 1979.89,2759.89 2075,2855 2510,2855 2592.56,2937.56 2592.56,3114.78 2595,3117.22 2595,3145 v1(2730,3280)
  Layer 4 - Bottom Layer w15: 2629.55,3139.55 C46.1@2735,3139.55
  Layer 4 - Bottom Layer w20: U11.1@2607.6,3094.29 2607.6,3101.44 2607.6,3117.6 2629.55,3139.55
  other v2: 2700,3280
  other v5: 2630,3205 2665,3205
AGND: C3.1 C4.2 C71.1 C72.1 C79.1 C80.1 C81.1 C82.1 C84.2 C85.2 C88.1 C89.2 C90.2 C91.1 C92.2 C93.2 C96.1 C97.1 C104.1 C105.1 C106.1 C107.1 C108.2 C109.2 C112.1 C115.2 C116.1 C117.2 C118.2 C119.2 C120.1 C121.2 C122.2 C284.2 C287.2 C288.2 C289.2 C304.2 C305.2 C306.2 C307.2 C308.2 C318.2 C320.1 C321.2 C449.1 C453.2 C454.2 C455.1 C457.2 C458.2 C459.2 CR479.2 CR481.2 FDA1.17 J14.2 J14.3 J14.4 J14.5 J15.2 J15.3 J15.4 J15.5 J18.2 J18.3 J18.4 J18.5 J19.2 J19.3 J19.4 J19.5 NT1.1 NT2.1 R3.1 R4.2 R110.1 R112.1 R113.1 R217.1 R268.1 R269.1 R284.1 R288.1 R454.1 R488.1 R491.1 TPAGND1.1 TPAGND2.1 TPAGND3.1 TPAGND4.1 TPAGND.1 U3.7 U3.8 U4.2 U414.2 U415.2 U422.4 UADS1.11 UADS1.15 UADS1.25 UADS2.11 UADS2.15 UADS2.25 | length 1836.9
  Layer 1 - Top Layer w10: UADS2.11@1760.2,1135.22 UADS2.25@1805.47,1135.22 ; UADS2.15@1825.16,1089.94 UADS2.25@1825.16,1154.9 ; UADS1.11@1985.2,2285.22 2030.47,2285.22 UADS1.25@2050.16,2304.9 ; UADS1.15@2050.16,2239.94 UADS1.25@2050.16,2304.9 ; v4(2060,2314.75) UADS1.25@2050.16,2304.9
  Layer 1 - Top Layer w17: R491.1@459.7,1611.24 491.2,1579.75 U415.2@515.87,1579.75 ; U415.2@513.26,1579.47 545.28,1579.47 558.33,1592.52 C449.1@558.33,1679.02 ; v1(1025,789.75) 1055,819.75 TPAGND4.1@1116.5,819.75 ; v2(1525,2692.75) TPAGND1.1@1625,2692.75
  Layer 1 - Top Layer w20: C320.1@875,1861.24 v1(875,1914.75) ; v1(900,1944.75) TPAGND3.1@1000,1944.75 ; R113.1@1266.5,1069.75 1266.5,1101.24 1275,1109.75 v1(1290,1109.75) ; R112.1@1266.5,1394.75 v5(1266.5,1424.75) ; C118.2@1443.5,1069.75 v1(1443.5,1099.75) ; C117.2@1443.5,1394.75 v1(1443.5,1424.75) ; v1(1666.38,1244.75) R288.1@1666.38,1274.75 ; v1(1773.5,2189.75) C89.2@1773.5,2224.75 ; C90.2@1773.5,2404.75 v1(1773.5,2439.75) ; v1(1891.38,2394.75) R284.1@1891.38,2429.75 ; v1(2030,2074.75) C88.1@2030,2113.25 ; TPAGND2.1@2160,1788.75 v1(2160,1888.75)
  Layer 1 - Top Layer w30: C105.1@861.5,844.75 v1(900,844.75) ; C107.1@861.5,1144.75 v1(901.5,1144.75) ; C82.1@861.49,2044.74 863.99,2047.25 v1(863.99,2071.94) ; C80.1@861.5,2344.75 v1(901.5,2344.75) ; C104.1@1085,1081.24 1113.5,1109.75 v1(1115,1109.75) ; C106.1@1085,1386.24 v1(1125,1386.24) ; C81.1@1085,2286.24 v1(1125,2286.24) ; C79.1@1085,2586.24 v1(1125,2586.24) ; v1(1675,1328.25) R269.1@1710,1328.25 ; v1(1805,924.75) C119.2@1805,963.25 ; v1(1900,2483.25) R268.1@1935,2483.25
  Layer 4 - Bottom Layer w10: 1081.5,904.75 R110.1@1138.5,904.75
  Layer 4 - Bottom Layer w20: v1(1018.5,844.75) 1018.5,904.75 C108.2@1018.5,959.75
  other v1: 1220,819.75 1220,849.75 1570,909.75 1984.45,914.74 1620,929.75 1570,939.75 1984.45,949.74 1620,964.75 1960,979.75 1630,1019.75 1163.5,1186.24 735.46,1187.35 1570,1214.75 1163.5,1216.24 1570,1244.75 1950,1339.75 1965,1389.75 1965,1424.75 2195,1703.75 1354.79,1750.16 1354.79,1780.16 1115,1785.01 1145,1785.01 1175,1785.01 1354.79,1810.16 2065,1834.75 2065,1859.75 1679.79,1870.16 1714.79,1870.16 2065,1884.75 1644.79,1905.16 1714.79,1920.16 1644.79,1940.16 2210,2069.75 1845,2079.75 2210,2104.75 1845,2114.75 1565,2124.75 1595,2139.75 2210,2139.75 1565,2154.75 1855,2169.75 1550,2189.75 1550,2219.75 2190,2474.75 2205,2524.75 2190,2544.75
  other v2: 905,1429.75 1459,1570 1354,1573 1354,1605 890,1679.75 559.83,1699.02 890,1709.75 500,1819.75 500,1869.75 500,1919.75
  other v4: 1835,1121.44 1791.69,1164.75 1835,1164.75 1878.31,1164.75 1835,1208.05 2060,2271.44 1421.3,2296.04 1458.7,2296.04 2016.69,2314.75 2103.31,2314.75 1421.3,2333.45 1458.7,2333.45 2060,2358.05
  other v5: 736,1050 945,1459.75 916.46,1529.75 545,1579.75 720,1669.75 890,1744.75 735,2253 735,2554
BCLK0_N: C64.1 U15.5@2990,1802.58 | length 116.9
  Layer 1 - Top Layer w5: U15.5@2990,1802.58 3027.33,1802.58 3034.5,1809.75 3034.5,1849.25 3015,1868.75 C64.1@3015,1871.12
BCLK0_P: C63.1 U15.4@3090,1802.58 | length 116.9
  Layer 1 - Top Layer w5: C63.1@3065,1871.13 3065,1868.75 3045.5,1849.25 3045.5,1809.75 3052.67,1802.58 U15.4@3090,1802.58
BCLK1_N: C64.2 R92.1 U33.6 | length 271.2
  Layer 1 - Top Layer w5: U33.6@2933.86,2071.36 2967.62,2071.36 2975,2078.75 3005.44,2078.75 3034.5,2049.68 3034.5,1985.25 R92.1@3019,1969.75 ; C64.2@3015,1918.37 3015,1920.74 3034.5,1940.25 3034.5,1955.25 3020,1969.75 R92.1@3019,1969.75 ; R92.1@3016.38,1969.75 R92.1@3019,1969.75
BCLK1_P: C63.2 R92.2 U33.5 | length 287.9
  Layer 1 - Top Layer w5: U33.5@2933.86,2096.95 2967.8,2096.95 2975,2089.75 3010,2089.75 3045.5,2054.24 3045.5,1985.25 3061,1969.75 R92.2@3063.63,1969.75 ; R92.2@3059,1969.75 3045.5,1956.25 3045.5,1940.25 3065,1920.75 C63.2@3065,1918.37
CONVST: J37.3 J38.3 R67.1 R78.1 TP7.1 TP35.1 U19.2 U32.2 | length 4240.8
  Layer 1 - Top Layer w10: TP35.1@2459.83,1166.75 U32.2@2459.83,1242.14 ; TP35.1@2460.3,1166.28 2583.47,1166.28 2625,1124.75 2734,1124.75 2750,1114.69 2750,1021.04 J38.3@2734.96,1006.01 3626.01,1006.01 3646.69,1026.69 R78.1@3706.4,1026.69 R78.1@3706.35,1026.75 ; U19.2@2867.81,2374.41 TP7.1@2867.81,2298.54 2923.8,2298.54 v2(2925,2299.75) ; J37.3@3389.96,2446.01 3420,2476.04 v2(3420,2499.75) 3423.75,2499.75 3590,2666 v2(3656,2666) 3656.39,2666.39 R67.1@3714.12,2666.39
  Layer 4 - Bottom Layer w10: v2(2925,2299.75) 3015,2389.75 3015,2514.75 3020,2519.75 3400,2519.75 v2(3420,2499.75) 3509,2410.75 3509,1008 v2(3510,1007)
CONVST_TO_DIF_ADC: J37.2 TP1.1 UADS1.1 | length 1720.7
  Layer 1 - Top Layer w10: UADS1.1@2109.21,2389.55 2184.8,2389.55 2215,2419.75 2335,2419.75 TP1.1@2400,2484.75 v1(2520,2484.75) ; v1(2835,2214.75) 2902.63,2214.75 2922.63,2234.75 3245,2234.75 3305,2294.75 3305,2519.71 J37.2@3310.04,2524.75
  Layer 4 - Bottom Layer w10: v1(2520,2484.75) 2750,2484.75 2815,2419.75 2815,2234.75 v1(2835,2214.75)
CONVST_TO_SE_ADC: J38.2 TP4.1 UADS2.1 | length 870.1
  Layer 1 - Top Layer w10: UADS2.1@1884.21,1239.55 1949.8,1239.55 1992.25,1282 2252.75,1282 2435,1099.75 TP4.1@2540,1099.75 2640.04,1099.75 J38.2@2655.04,1084.75
CONVSTN_DIF: TP2.1 U18.1 U19.4 | length 326.1
  Layer 1 - Top Layer w10: U19.4@2905.21,2482.68 2947.64,2482.68 2980,2515.04 TP2.1@3125,2515.04 3125,2424.44 U18.1@3123.4,2422.84
CONVSTN_SE: TP34.1 U31.1 U32.4 | length 379.1
  Layer 1 - Top Layer w10: U32.4@2497.23,1350.41 2530.67,1350.41 2620,1439.75 TP34.1@2720,1439.75 2720,1394.75 2740.8,1373.94 U31.1@2740.8,1329.04
CSN: R68.1 R79.1 UADS1.24 UADS2.24 | length 5423.1
  Layer 1 - Top Layer w10: UADS2.24@1909.8,1213.96 1954.21,1213.96 2005,1264.75 2225,1264.75 2515,974.75 3644.75,974.75 3651.69,981.69 R79.1@3706.4,981.69 ; UADS1.24@2134.8,2363.96 2189.21,2363.96 2225,2399.75 2481.51,2399.75 2546,2464.24 v2(2546,2537) 2546,2579.53 2707.86,2741.39 3465.61,2741.39 v2(3547,2660) ; v2(3657,2620) 3658.39,2621.39 R68.1@3714.12,2621.39 R68.1@3713.73,2621
  Layer 4 - Bottom Layer w10: v2(2546,2537) 2526,2537 2485,2496 2485,2329 2557,2257 v2(2557,980) v2@2557,976 ; v2(3547,2660) 3587,2620 v2(3657,2620)
EVM_DVDD_0: C22.1 C266.1 J4.50 | length 204
  Layer 1 - Top Layer w10: v1(3866.7,2279.29) J4.50@3920.51,2279.29
  Layer 4 - Bottom Layer w20: v1(3866.7,2279.29) 3900.02,2245.96 3900.02,2154.9 C22.1@3891.52,2146.39
EVM_DVDD_1: C21.1 C268.1 J7.50 | length 203.5
  Layer 1 - Top Layer w10: v1(3875.21,639.59) J7.50@3928.52,639.59
  Layer 4 - Bottom Layer w20: v1(3875.21,639.59) 3908.53,606.27 C268.1@3908.53,576.69 3908.53,515.2 C21.1@3900.03,506.69
EVM_ID_PWR_0: C53.2 C58.1 C259.1 C271.1 J4.59 R64.2 U13.1 U13.8 | length 1025.4
  Layer 1 - Top Layer w10: v1(4107.01,2166.39) 4121.4,2180.79 J4.59@4163.51,2180.79
  Layer 4 - Bottom Layer w30: 3897,2552.4 3943,2552.4 3997,2606.4 C271.1@3997,2616.4 4005.63,2607.77 C53.2@4062,2607.77 4117,2552.77 4117,2552.4 4206,2552.4 4227.01,2531.39 R64.2@4227.01,2482.89 4270.51,2482.89 4282.01,2471.39 4282.01,2361.39 4242.01,2321.39 4157.01,2321.39 4137.01,2301.39 C58.1@4137.01,2236.39 4145.51,2227.89 C259.1@4145.51,2166.39 v1(4107.01,2166.39)
EVM_ID_PWR_1: C55.2 C60.1 C260.1 C272.1 J7.59 R87.2 U14.1 U14.8 | length 995.7
  Layer 1 - Top Layer w10: v1(4110.02,526.69) 4124.42,541.09 J7.59@4171.52,541.09
  Layer 4 - Bottom Layer w30: 3890.02,877.69 3946.04,877.69 3990.02,921.68 3990.02,941.69 3998.65,933.07 4063.65,933.07 4119.02,877.69 4199.02,877.69 4220.03,856.69 R87.2@4220.03,798.19 4258.53,798.19 4270.02,786.69 4270.02,686.69 4250.02,666.69 4150.02,666.69 4135.03,651.7 C60.1@4135.03,596.69 4143.54,588.19 C260.1@4143.54,526.69 v1(4110.02,526.69)
EVM_REG_5V5_0: C57.1 C267.1 J4.1 | length 169.3
  Layer 1 - Top Layer w10: v1(4101.51,2752.09) J4.1@4163.51,2752.09
  Layer 4 - Bottom Layer w20: v1(4101.51,2752.09) 4134.34,2752.09 4135.02,2751.4 4135.02,2689.89 C57.1@4126.52,2681.39
EVM_REG_5V5_1: C59.1 C269.1 J7.1 | length 168.8
  Layer 1 - Top Layer w10: v1(4110.02,1112.39) J7.1@4171.52,1112.39
  Layer 4 - Bottom Layer w20: v1(4110.02,1112.39) 4142.85,1112.39 C269.1@4143.54,1111.71 4143.54,1050.2 C59.1@4135.03,1041.69
FB_3P3V: Cff3.2 Rfbb3.2 Rfbt3.1 U5.6 | length 358.8
  Layer 1 - Top Layer w30: Rfbb3.2@2353,245 Rfbt3.1@2423.5,245 ; Cff3.2@2423.5,168.5 Rfbt3.1@2423.5,245 ; U5.6@2582.37,329 2476.5,329 2423.5,276.01 Rfbt3.1@2423.5,245
FB_5V: Cff2.2 Rfbb5.2 Rfbt2.1 U23.6 | length 423.7
  Layer 1 - Top Layer w30: Rfbb5.2@3095,3460 3171.83,3460 3175.53,3456.3 3294.47,3456.3 3298.17,3460 U23.6@3394.37,3460 ; Cff2.2@3248.5,3331.5 Rfbt2.1@3248.5,3400 3248.5,3452.8
FB_18V: Cff.2 Rfbb.2 Rfbt.1 U22.6 | length 213.9
  Layer 1 - Top Layer w25: U22.6@719.63,3208 Rfbt.1@809.5,3208 ; Rfbt.1@815,3213.5 Cff.2@875,3213.5 880,3208.5 Rfbb.2@880,3151.5
GND: C1.2 C9.2 C10.2 C11.2 C12.2 C13.2 C14.2 C15.1 C16.2 C17.2 C18.2 C19.1 C20.2 C21.2 C22.2 C23.2 C24.2 C25.2 C26.2 C27.2 C28.2 C31.2 C32.2 C33.2 C41.1 C42.1 C45.2 C47.2 C53.1 C54.1 C55.1 C56.1 C57.2 C58.2 C59.2 C60.2 C61.2 C62.2 C94.1 C95.1 C259.2 C260.2 C261.2 C262.2 C266.2 C267.2 C268.2 C269.2 C271.2 C272.2 C290.2 C291.1 C338.2 C339.2 C340.2 C343.2 C344.1 C345.1 C346.1 C347.2 C348.2 C349.2 C350.2 C351.2 C352.2 C353.2 C354.2 C355.2 C356.2 C357.2 C358.2 C359.2 C360.2 C362.2 C364.2 C366.2 C367.2 C368.2 C369.2 C370.2 C371.2 C372.2 C375.2 C376.2 C378.2 C379.2 C380.2 C381.2 C382.2 C383.2 C384.2 C388.2 C389.2 C391.2 C401.2 C402.2 C405.1 C406.1 C409.1 Cin1.2 Cin2.2 Cin3.2 Cin.2 Cout1.2 Cout2.2 Cout3.2 Cout4.2 Cout5.2 Cout6.2 Css2.2 Css3.2 Css.1 CVCC3V.2 CVCC5V.2 CVCC18V.2 D14.1 D18.1 D22.1 GNDin.1 J3.1 J4.60 J4.MP1 J4.MP2 J4.MP3 J4.MP4 J5.2 J6.2 J7.60 J7.MP1 J7.MP2 J7.MP3 J7.MP4 J8.1 J39.3 L1.2 L401.2 NT1.2 NT2.2 R8.1 R9.1 R10.1 R11.1 R12.1 R13.1 R14.1 R15.1 R17.1 R18.1 R19.1 R20.1 R21.1 R24.1 R25.1 R26.1 R27.1 R29.1 R30.1 R31.1 R32.1 R33.1 R34.1 R35.1 R36.1 R41.2 R44.1 R90.1 R246.2 R279.1 R280.1 R290.1 R294.1 R297.1 R402.2 Renb2.1 Renb3.1 Renb.1 Rfbb3.1 Rfbb5.1 Rfbb.1 TPGND1.1 TPGND2.1 TPGND3.1 TPGND4.1 TPGND.1 U3P8V.5 U3P8V.6 U3P8V.7 U3P8V.8 U3P8V.10 U3P8V.11 U3P8V.12 U3P8V.13 U3P8V.16 U3P8V.17 U3P8V.20 U5.4 U5.8 U5P5V.5 U5P5V.6 U5P5V.7 U5P5V.8 U5P5V.10 U5P5V.11 U5P5V.12 U5P5V.13 U5P5V.16 U5P5V.17 U5P5V.20 U6.2 U6.7 U6.17 U6.18 U6.19 U6.21 U7.2 U7.7 U7.17 U7.18 U7.19 U7.21 U8.2 U8.7 U8.17 U8.18 U8.19 U8.21 U9.11 U10.2 U10.5 U11.4 U11.9 U15.3@3090,1656.91 U18.3 U18P5V.5 U18P5V.6 U18P5V.7 U18P5V.8 U18P5V.10 U18P5V.11 U18P5V.12 U18P5V.13 U18P5V.16 U18P5V.17 U18P5V.20 U19.3 U22.4 U22.8 U23.4 U23.8 U31.3 U32.3 U33.1 U33.9 U33.13 U401.5 | length 9291.5
  Layer 1 - Top Layer w10: v1(1740,78.98) C19.1@1740,137.48 ; 2542,3633 2573.11,3601.89 2590,3601.89 ; C15.1@3046.02,3145.15 3070.87,3170 v1(3110,3170) ; v1(3827.01,2171.39) 3836.4,2180.79 J4.60@3920.51,2180.79 ; v1(3845.02,526.69) 3859.42,541.09 J7.60@3928.52,541.09
  Layer 1 - Top Layer w15: v1(2444,2711) 2444,2700 2462.5,2681.5 D18.1@2486,2681.5 ; U32.3@2497.23,1242.14 2497.23,1271.98 v1(2530,1304.75) ; U33.1@2933.86,2199.31 2985.43,2199.31 v1(2995,2189.75) ; U33.9@3166.14,2020.18 v1(3205,2020.18) ; U33.13@3166.14,2122.54 v1(3205,2122.54) ; TPGND1.1@3378.02,408 3378.02,316.98 v1(3380,315)
  Layer 1 - Top Layer w20: C11.2@1720,3130 v1(1720,3180) ; v1(2350,115) D14.1@2350,160 ; TPGND2.1@2450,1779.75 v1(2450,1889.75) ; v1(2660.21,1329.04) U31.3@2685.21,1329.04 ; R246.2@2785,3336.5 v5@2860,3261.5 ; v1(2790.01,1584.75) C62.2@2823.5,1584.75 ; v1(2820,1959.75) C339.2@2820,1998.25 ; v1(2870,1974.74) C340.2@2870,2006.13 ; U19.3@2905.21,2374.41 v1(2932.81,2374.41) ; v1(3047.81,2423.57) U18.3@3067.81,2423.57 ; U15.3@3090,1656.91 v1(3135,1656.91) ; R90.1@3103.62,1589.75 v1(3140,1589.75) ; v1(3385,1305) TPGND4.1@3385,1425 ; TPGND3.1@3540,2990 v1(3645,2990)
  Layer 1 - Top Layer w25: Rfbb5.1@3095,3540 3132.5,3502.5 3203.5,3502.5 Css2.2@3203.5,3495
  Layer 1 - Top Layer w30: C61.2@2823.5,1874.74 v1(2823.5,1909.74)
  Layer 3 - PWR w80: 663.55,600 455,600 439.47,615.53 286.26,615.53 54,847.79 54,3261 668,3875 1163.43,3875 J8.1@1303.43,3735
  Layer 4 - Bottom Layer w10: CVCC18V.2@810,3098.5 CVCC18V.2@818.5,3090 ; U18P5V.20@878.46,3090 910,3090 913.9,3086.1 U18P5V.16@913.9,3015.2 U18P5V.17@891.26,3015.2 ; CVCC3V.2@981.81,355 U3P8V.20@1038.46,355 ; v2(1070,355) 1073.9,351.1 U3P8V.16@1073.9,280.2 ; U8.7@1765.59,2948.46 U8.21@1765.59,3014.41 ; U8.21@1765.59,3065.59 U8.2@1831.54,3065.59 ; U6.7@1935.59,93.46 U6.21@1935.59,159.41 ; U6.21@1935.59,210.59 U6.2@2001.54,210.59 ; 2570,3537.2 2618.5,3488.7 C405.1@2618.5,3485 ; U7.7@2813.46,2954.41 U7.21@2879.41,2954.41 ; U7.2@2930.59,2888.46 U7.21@2930.59,2954.41 ; 2941.72,599.98 2976.04,599.98 2983.02,593 ; U10.2@3184.9,415.32 3184.9,350.64 3185.81,349.72 ; U10.2@3185.81,415.32 3185.81,349.72 ; v1(3243.02,328) 3207.53,328 3185.81,349.72 ; C27.2@3269.51,663 3279.51,653 v1(3313.02,653) ; C28.2@3269.51,718 v1(3301.04,718) ; 3591.1,3583.9 3595,3580 U5P5V.20@3626.54,3580 ; U5P5V.16@3591.1,3654.8 3591.1,3721.1 3630,3760 3630,3790 ; CVCC5V.2@3686.5,3580 CVCC5V.2@3695,3571.5
  Layer 4 - Bottom Layer w13: 1040,80 1040,177 1073.9,210.9 U3P8V.16@1073.9,280.2
  Layer 4 - Bottom Layer w15: U401.5@2521.14,3537.2 2570,3537.2
  Layer 4 - Bottom Layer w20: v1@1878.5,463.5 C353.2@2140,463.5 ; v4(1910,185) U6.21@1935.59,210.59 ; 2080,440 C353.2@2103.5,463.5 ; v1(2995,2044.75) C350.2@3029.93,2044.75 ; v1(2995,2189.75) 3008.5,2176.24 C348.2@3008.5,2149.75 3015,2143.25 v1(3015,2119.75) 3015,2104.68 C349.2@3029.93,2089.75 ; C266.2@3963.5,2221.39 v1(4007.01,2221.39) ; C268.2@3971.52,576.69 v1(4015.02,576.69) C261.2@4015.02,641.69 ; C22.2@3972.01,2151.39 v1(4007.01,2151.39) ; C21.2@3980.03,506.69 v1(4015.02,506.69) ; C271.2@3997,2696.4 4007.01,2696.4 4027,2716.39 v1(4041.52,2716.39) ; C272.2@4000.02,1016.69 4015.02,1031.69 v1(4015.02,1061.69) ; v1(4012.01,2276.39) C262.2@4012.01,2316.39 ; C53.1@4062,2655.02 v1(4062,2696.4) ; C55.1@4065.02,980.32 4065.02,1006.69 v1(4085.02,1026.69) ; v1(4077.01,2276.39) C54.1@4077.01,2312.77 ; v1@4078.39,2426.39 R279.1@4098.39,2406.39 ; v1(4080.03,606.7) C56.1@4080.03,638.07 ; v1(4085.02,751.69) 4086.4,751.69 R280.1@4106.4,731.69 ; C259.2@4208.5,2166.39 v1(4242.01,2166.39) ; C58.2@4217.01,2236.39 v1(4257.01,2236.39)
  Layer 4 - Bottom Layer w30: C267.2@4198.5,2751.39 v1(4232.01,2751.39) ; C260.2@4206.53,526.69 v1(4240.04,526.69) ; C269.2@4206.53,1111.71 v1(4240.03,1111.71) ; C57.2@4207.01,2681.39 v1(4247.01,2681.39) ; C60.2@4215.03,596.69 v1(4255.04,596.69) ; C59.2@4215.03,1041.69 v1(4255.04,1041.69)
  other v1: 2235,115 1310,175 1575,345 1575,375 1830,465 1880,465 1930,465 1980,465 1240,495 1830,515 1880,515 1930,515 1980,515 1240,525 1425,545 1470,545 1515,545 1270,560 4050.03,576.7 640,583 675,583 3063.02,608 3088.02,608 457,613 495,613 540,613 595,613 640,613 675,613 3020,639.63 3051.04,663 3020,685 3051.04,718 4050.03,826.7 4050.03,1076.7 2900.21,1289.75 2900.21,1319.75 2484.83,1521.3 2514.83,1521.3 2613,1794.75 2613,1819.75 2613,1844.75 4041.51,2066.39 2650,2109.74 2685,2109.74 4041.51,2216.39 4077.01,2426.39 3215,2445.04 3245,2445.04 4041.52,2466.39 3215,2475.04 3245,2475.04 2880,2654.75 2905,2654.75 1295,2840 1353,2840 1120,2860 4041.51,2866.39 2085,2920 1095,2970 1120,2970 1095,2995 2430,3140 2540,3140 2430,3165 2540,3165 2907,3265 1530,3275 1135,3300 1230,3300 1530,3300 4150,3305 4190,3305 1155,3325 1185,3325 1215,3325 1245,3325 1790,3335 1825,3335 1860,3335 1890,3335 4150,3340 4190,3340 4150,3370 4190,3370 4150,3405 4190,3405 1305,3645 1305,3675 1340.69,3677.89 1370.69,3677.89 1400.69,3677.89 1430.69,3677.89 1460.69,3677.89 1370.69,3707.89 1400.69,3707.89 1430.69,3707.89 1460.69,3707.89 2930,3715 2960,3715 2065,3740 2065,3765 2930,3765 2065,3790 730,3865 670,3905
  other v2: 1270,95 1270,125 1270,155 825,185 2703,190 2736,190 2766,190 2797,190 2829,190 2704,222 2735,222 2768,222 2793,223 2826,223 2856,223 2887,223 2919,223 2794,255 2825,255 2858,255 2888,255 2921,255 2952,255 1310,265 1270,275 2827,287 2859,287 2890,287 2920,287 2953,287 834,306 1095,335 834,365 833,426 1310,440 833,485 1455,2825 1265,2840 1455,2855 865,2945 1120,2995 1400,3015 615,3165 615.3,3196 615,3225 615.3,3255 1305,3280 1200,3300 3145,3305 3170,3305 3200,3305 1925,3335 1970,3335 3170,3335 3200,3335 3145,3360 3460,3370 3145,3385 2990,3390 3145,3415 3875,3430 2990,3435 3875,3455 3875,3485 2990,3510 3875,3515 2585,3522.2 2738,3522 2793,3523 2765,3530 2818,3532 2990,3540 3875,3545 2793,3553 2765,3560 2818,3562 3875,3575 2793,3578 2765,3585 2818,3587 3875,3605 2793,3608 2765,3615 2818,3617 3875,3635 2793,3638 2765,3645 2925,3645 2970,3645 3010,3645 2818,3647 3875,3665 2925,3675 2970,3675 3010,3675 3875,3695 3875,3725 2930,3740
  other v3: 1240,185 1240,215 1240,245 1335,245 1270,440 1360,440 1240,465 1230,560 457,583 495,583 540,583 595,583 1120,2835 1325,2840 1120,2885 1390,3190 2035,3270 1265,3280 1345,3280 1170,3300 2015,3335 3145,3335 3460,3340 3170,3360 3170,3385 2990,3480 3465,3480 3139.15,3649.13 2065,3687 2065,3715 2960,3740 2960,3765 2190,3775 2930,3790 2960,3790 670,3865 700,3865 700,3905 730,3905
  other v4: 1910,132.83 1855,185 1962.17,185 1910,237.17 2905,2927.83 2852.83,2980 2905,2980 2957.17,2980 1740,2987.83 2502.28,3026.38 2537.72,3026.38 2905,3032.17 1687.83,3040 1740,3040 1792.17,3040 2520,3050 2502.28,3073.62 2537.72,3073.62 1740,3092.17
  other v5: 2645,2860 2645,2895 2085,2945 2085,2975 2860,3265
NetC4_1: C4.1 U3.4 | length 87.8
  Layer 1 - Top Layer w10: C4.1@1451.5,1750.16 1484.79,1750.16 1501.4,1766.77 U3.4@1532.4,1766.77
NetC5_1: C5.1 R56.1 U3.5 U3.6 | length 100.2
  Layer 1 - Top Layer w40: C5.1@1814.75,1769.75 R56.1@1915,1769.75
NetC5_2: C5.2 R4.1
NetC11_1: C11.1 U8.14 | length 108.2
  Layer 1 - Top Layer w10: v1(1615,3065) 1615,3105 C11.1@1640,3130
  Layer 4 - Bottom Layer w10: v1(1615,3065) U8.14@1647.87,3065
NetC15_2: C15.2 U7.14 | length 172.5
  Layer 1 - Top Layer w10: v1(2925,3110) 2945,3110 2972.84,3082.16 C15.2@3046.02,3082.16
  Layer 4 - Bottom Layer w10: v1(2925,3110) 2925,3077.13 U7.14@2930,3072.13
NetC19_2: C19.2 U6.14 | length 71.8
  Layer 1 - Top Layer w10: C19.2@1748.5,215 v1(1785,215)
  Layer 4 - Bottom Layer w10: v1(1785,215) 1814.06,215 U6.14@1818.46,210.59
NetC25_1: C25.1 C26.1 R22.1 U10.6 | length 223.3
  Layer 4 - Bottom Layer w10: U10.6@3160.22,580.68 3160.22,647.29 C25.1@3144.51,663 C26.1@3144.51,718 3144.51,748 R22.1@3179.51,783
NetC27_1: C27.1 C28.1 U10.7 | length 145.9
  Layer 4 - Bottom Layer w10: U10.7@3185.81,580.68 3185.81,642.29 C27.1@3206.52,663 C28.1@3206.52,718
NetC29_1: C29.1 C30.1 U10.1 | length 208.1
  Layer 4 - Bottom Layer w10: U10.1@3210.49,415.32 3210.49,450.47 ; U10.1@3211.4,415.32 3211.4,449.55 3210.49,450.47 ; C30.1@3340.07,466.5 C29.1@3283.02,466.5 3281.52,468 3228.02,468 3210.49,450.47
NetC29_2: C29.2 C30.2 U10.8 | length 173
  Layer 4 - Bottom Layer w10: U10.8@3211.4,580.68 3211.4,546.39 3210.49,545.47 3227.95,528 3281.52,528 C29.2@3283.02,529.5 C30.2@3340.07,529.5
NetC31_1: C31.1 C32.1 C43.1 JMTI_-18V.1 U9.3 | length 136.2
  Layer 1 - Top Layer w20: C43.1@1876.57,3733.39 U9.3@2012.8,3733.39
NetC33_1: C33.1 L4.1 U10.4
NetC35_1: C35.1 R45.1 U9.1 | length 139.9
  Layer 1 - Top Layer w10: R45.1@1991.5,3855 2038.5,3855 C35.1@2058.5,3835 U9.1@2012.8,3789.29
NetC37_1: C37.1 R45.2 U9.8 | length 503.5
  Layer 1 - Top Layer w10: R45.2@1928.5,3855 1925,3855 1925,3829.14 1935,3819.14 1935,3799.82 1944.82,3790 v2(1945,3790) ; C37.1@2012.8,3560.48 U9.8@2012.8,3605.43 ; U9.8@2017.36,3610 v2(2064.31,3610)
  Layer 4 - Bottom Layer w10: v2(1945,3790) 1920,3765 1920,3610 v2(2064.31,3610)
NetC38_1: C38.1 C39.1 R41.1 R42.2 U9.6 | length 535.2
  Layer 1 - Top Layer w10: R41.1@1701.5,3470 C39.1@1701.51,3527.8 ; C39.1@1704.31,3525 1811.61,3525 1820,3533.39 1820,3630 1846.61,3656.61 U9.6@2012.8,3656.61 ; R42.2@1763.5,3465 C38.1@1763.5,3522.82
NetC38_2: C38.2 R40.1 U9.5 | length 353.7
  Layer 1 - Top Layer w10: R40.1@1701.51,3587.8 1758.52,3587.8 C38.2@1760.02,3589.3 1760.02,3595.02 1847.2,3682.2 U9.5@2012.8,3682.2
NetC39_2: C39.2 R40.2 | length 60
  Layer 1 - Top Layer w10: C39.2@1638.52,3527.8 R40.2@1638.52,3587.8
NetC40_2: C40.2 U9.16 | length 2.5
  Layer 1 - Top Layer w10: C40.2@2237.2,3825.71 C40.2@2239,3827.5
NetC45_1: C45.1 U11.6 | length 120.5
  Layer 1 - Top Layer w10: v1(2380,3045) 2380,3040.07 2385.42,3045.49 C45.1@2437.74,3045.49
  Layer 4 - Bottom Layer w10: v1(2380,3045) 2387.8,3037.2 U11.6@2432.4,3037.2
NetC46_2: C46.2 R43.1 R44.2 U11.2 | length 193.4
  Layer 4 - Bottom Layer w20: U11.2@2607.6,3062.8 2642.8,3062.8 2655.85,3075.85 R43.1@2680,3075.85 ; R44.2@2680,3014.55 R43.1@2680,3075.85 ; C46.2@2734.29,3075.85 R43.1@2680,3075.85
NetC83_1: C83.1 R99.1 | length 57
  Layer 1 - Top Layer w8: R99.1@1270,2286.24 C83.1@1270,2343.25
NetC83_2: C83.2 C317.2 FDA1.2 RDN2.1 RMFBN2.1 | length 270.2
  Layer 1 - Top Layer w8: RMFBN2.1@1331,2467.38 1328.37,2464.75 RDN2.1@1271.5,2464.75 1270,2463.25 C83.2@1270,2406.24 1330,2346.24 C317.2@1330,2343.25 1348.66,2324.59 FDA1.2@1384.88,2324.59
NetC86_1: C86.1 R101.1 R104.1 R212.2 | length 179
  Layer 1 - Top Layer w8: R212.2@1598.62,2339.75 1646.5,2339.75 C86.1@1655,2348.25 R101.1@1715,2348.25 1772.01,2348.25 R104.1@1773.5,2349.75
NetC86_2: C86.2 R101.2 RMFBN2.2 RMFBN.2 | length 558.5
  Layer 1 - Top Layer w8: RMFBN.2@1256.62,2520.55 RMFBN.2@1262.55,2514.62 ; C86.2@1654,2412.24 C86.2@1655,2411.24 R101.2@1715,2411.24
  Layer 1 - Top Layer w10: RMFBN.2@1262.55,2514.62 RMFBN2.2@1331,2514.62 1367.62,2514.62 1392,2539 1585,2539 1655,2469 1655,2413.24 C86.2@1654,2412.24
NetC87_1: C87.1 R100.1 R103.1 R211.2 | length 179
  Layer 1 - Top Layer w8: R211.2@1598.62,2289.75 1646.5,2289.75 C87.1@1655,2281.24 R100.1@1715,2281.24 1772.01,2281.24 R103.1@1773.5,2279.75
NetC87_2: C87.2 R100.2 RMFBP2.1 RMFBP.1 | length 557.4
  Layer 1 - Top Layer w8: C87.2@1654,2217.25 C87.2@1655,2218.25 R100.2@1715,2218.25
  Layer 1 - Top Layer w10: RMFBP.1@1256.62,2110 1324.62,2110 RMFBP2.1@1329,2114.38 1366.23,2114.38 1390.86,2089.75 1584.14,2089.75 1654,2159.6 C87.2@1654,2217.25
NetC88_2: C88.2 UADS1.13 UADS1.14
NetC89_1: C89.1 C315.1 R103.2 UADS1.10 | length 209.2
  Layer 1 - Top Layer w8: C89.1@1836.5,2224.75 R103.2@1836.5,2279.75 C315.1@1891.5,2279.75 ; C315.1@1895,2283.25 1916.65,2304.9 UADS1.10@1985.2,2304.9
